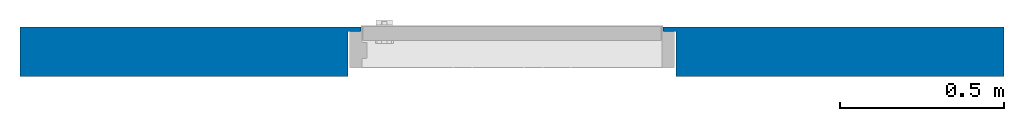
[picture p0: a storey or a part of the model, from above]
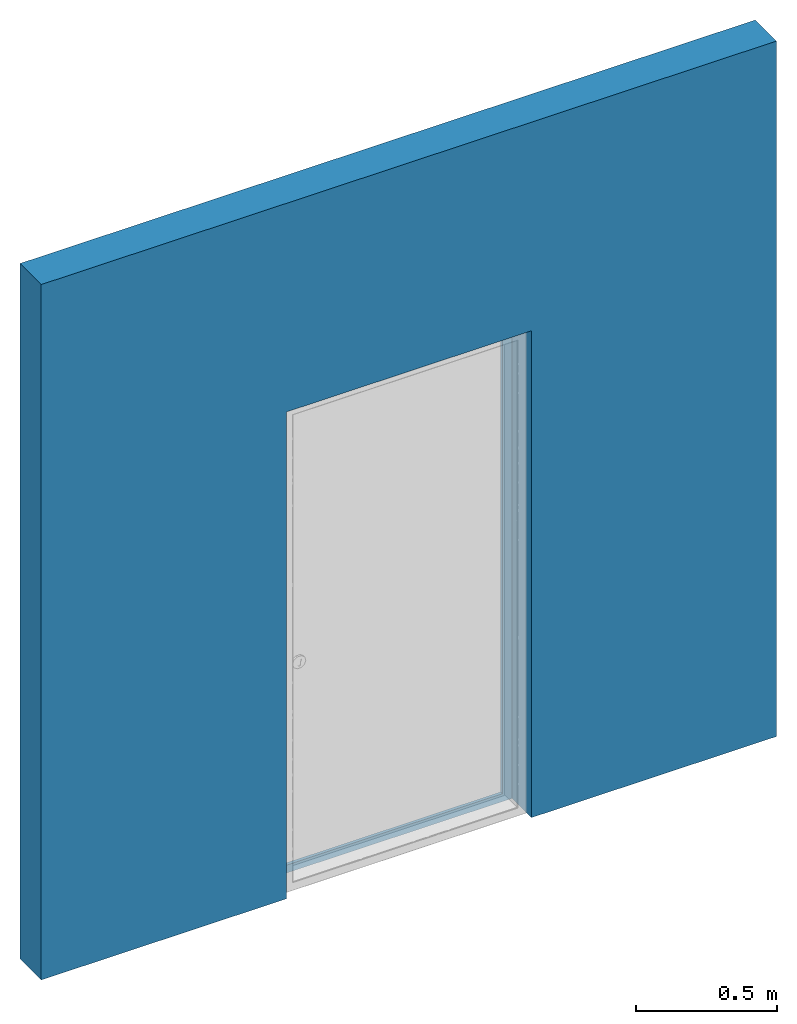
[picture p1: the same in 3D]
Properties of the parts of a building model (IFC2X3)

# File
Description: ViewDefinition [CoordinationView_V2.0]
Time: 2015-03-31T12:31:44
Written by: The EXPRESS Data Manager Version 5.01.0100.02.64mod : 6 Jun 2012
Made in: 20130709_2115(x64) - Exporter 3.12.0.0 - Alternate UI 2.12.0.0
Comment: STEP Physical File produced by: The EXPRESS Data Manager Version 5.01.0100.02.64mod : 6 Jun 2012 * Module: EDMstepFileFactory/EDMstandAlone * Creation date: Tue Mar 31 12:31:44 2015 * Host: NCL-TA29 * Database: C:\Users\Vickersc\AppData\Local\Temp\{78927F32-97B8-4338-B3C9-AA30E305E44B}\ifc * Database version: 5507 * Database creation date: Tue Mar 31 12:31:42 2015 * Schema: IFC2X3 * Model: DataRepository.ifc * Model creation date: Tue Mar 31 12:31:43 2015 * Header model: DataRepository.ifc_HeaderModel * Header model creation date: Tue Mar 31 12:31:43 2015 * EDMuser: sdai-user * EDMgroup: sdai-group * License ID and type: 5605 : Permanent license. Expiry date: * EDMstepFileFactory options: 020000

# IfcProject
LongName: X:\NBL\Manufacturer\A\Assa Abloy 0060A_8204\WIP\Xbim\Batch1\IFC\NBS_AssaAbloyLtd_DrsetSym_AASDMetalRiserDoor-Hingeless_Single.ifc

# IfcSite, Default
RefLatitude: 42, 24, 53, 508911; RefLongitude: -71, -15, -29, -58837; RefElevation: 0 mm

# IfcBuildingStorey, Level 1
LongName: Level 1; Elevation: 0 mm

# IfcDoor: 1000x2100mm, NBS_AssaAbloyLtd_DrsetSym_AASDMetalRiserDoor-Hingeless_Single:1000x2100mm:12042
In: Level 1
Type - ParameterTakesPrecedence: no; Sizeable: no; Material: NBS_Concept
Type - Pset_DoorCommon - AcousticRating: Unrated; FireExit: no; FireRating: Certifire CF520 tested up to 240 minutes (dependant on configuration); GlazingAreaFraction: 0; HandicapAccessible: yes; HasDrive: no; Infiltration: 0 m3/s; IsExternal: no; Reference: n/a; SecurityRating: Unrated; SelfClosing: no; SmokeStop: no; ThermalTransmittance: 0 kg/K/s3
Type - COBie - AccessibilityPerformance: n/a; CodePerformance: n/a; Constituents: n/a; Features: n/a; Finish: n/a; Grade: n/a; Manufacturer: sales@assaabloy.co.uk; Material: n/a; ModelReference: AASD Metal Riser Door - Hingeless; NominalHeight: 2100 mm; NominalLength: 0 mm; NominalWidth: 1000 mm; ReplacementCost: n/a; Shape: Rectangle; Size: 1000 x 2100 mm; SustainabilityPerformance: n/a; WarrantyDescription: n/a; WarrantyDurationParts: n/a; WarrantyGuarantorParts: n/a; AssetType: Fixed; Category: n/a; DurationUnit: year; Name: DoorsetSystem_AASDMetalRiserDoor-Hingeless_Single-1000x2100mm_AssaAbloyLtd; WarrantyDurationUnit: year; ExpectedLife: n/a; Description: Single metal door for access to risers; Color: n/a; ModelNumber: n/a; WarrantyDurationLabor: n/a; WarrantyGuarantorLabor: n/a
Type - NBS_General - Revision: n/a; NBSOfficeMasterTag: n/a; Author: NBS; BIMObjectName: NBS_AssaAbloyLtd_DoorsetSystem_AASDMetalRiserDoor-Hingeless_Single-1000x2100mm; ManufacturerName: Assa Abloy Ltd; ManufacturerURL: www.assaabloy.co.uk; NBSCertification: www.nationalbimlibrary.com/assa-abloy/single-hingeless-metal-riser-door; NBSDescription: Doorset system; NBSNote: 25-90-20/120; NBSReference: 25-50-20/120; NBSTypeID: n/a; Uniclass2: 25-30-20/120; Version: 2; ProductInformation: www.assaabloy.co.uk/en/local/uk/About-ASSA-ABLOY/UK-organisation/Security-Doors/Products1/Powershield-Doors/
Type - NBS_Data - DoorstopOptions: Floor mounted door stop, Wall mounted door stop.; FireRatingOptions: Unrated, 30 minutes, 60 minutes, 120 minutes, 240 minutes; FrameFinishOptions: Epoxy powder primed, Polyester powder coated, Satin polish 180-240 grit (stainless steel only), Patterned finish (stainless steel only), Laminates; FrameMaterialOptions: Steel Galvatite ZF ‘Galvanneal’, Stainless Steel Grade 304, Stainless Steel Grade 316; FrameProfileOptions: Bespoke frame; FrameWidthOptions: Available from 140mm.; HardwareSetOptions: Hardware Set 1 (DT-HW-R1) Hardware Set 2 (DT-HW-R2); LeafFacingOptions: Epoxy powder primed, Polyester powder coated, Satin polish 180-240 grit (stainless steel only), Patterned finish (stainless steel only), Laminates; LeafMaterialOptions: Steel Galvatite ZF ‘Galvanneal’, Stainless Steel Grade 304, Stainless Steel Grade 316; LeafSwingOptions: Inward opening, Outward opening; MaximumStructuralOpening: 1400 x 3000 mm; MinimumStructuralOpening: 500 x 1000 mm; OperationOptions: AASD PP002, AAUK EPCP001, AAUK PH002BT; SecurityRatingOptions: Various security enhancements are available, please contact ASSA ABLOY Security Doors for more details; SuitableLocation: Riser; ThermalTransmittanceOptions: 3.7 (Optional upgrade to 1.7, please contact ASSA ABLOY Security Doors for more details); VisionPanelOptions: Standard Louvre - Double; AdditionalHardware: n/a; AlternativeDoorsetGlazing: n/a; BreakoutFacility: no; DoorSeal: no; DoorsetFasteners: AASD Bespoke frame adjusters with specialised screw fixings for masonry, timber or metal; DoorsetType: Metal; FrameRevealFiller: n/a; FrameSeal: yes; OverPanels: n/a; SidePanels: n/a; SystemAccessories: n/a; ThresholdBase: n/a; ThresholdStripping: no; Trim: n/a; AirTransferGrille: no; AirTransferGrilleSize: n/a; AntiFingerTrapRequirement: no; Configuration: Single leaf, single action; FrameFinish: n/a; FrameMaterial: n/a; FrameProfile: n/a; GlassType: n/a; ThresholdRequired: no; VisionPanelConfiguration: n/a; AutomaticHardware: n/a; EmergencyPanicOperation: n/a; Hanging: n/a; Operating: n/a; PlatesAndStops: AAUK EPCE001; Securing: AAUK ECT001, AAUK MDL001
OverallHeight: 2100 mm; OverallWidth: 1000 mm
COBie - AssetIdentifier: n/a; BarCode: n/a; InstallationDate: 1900-12-31T23:59:59; SerialNumber: n/a; TagNumber: n/a; WarrantyStartDate: 1900-12-31T23:59:59
NBS_Data - ComponentNumber: n/a; DoorNumber: n/a; ElectronicLock: no; FloorFinish: n/a; Handing: n/a; HardwareSet: DT-HW-R1; HeadDetail: n/a; HoldOpen: no; JambDetail: n/a; KeySuiting: n/a; LeafEdgings: n/a; LeafFacing: n/a; LeafSwing: n/a; OpeningMechanism: no; SignageFire: n/a; SignageSecurity: n/a; SignageWayfinding: n/a

# IfcWallStandardCase: Basic Wall:NBS_Int_Concept, Basic Wall:NBS_Int_Concept:2301
In: Level 1
Type - PredefinedType: STANDARD; Material: nbl_Concept 150 mm
